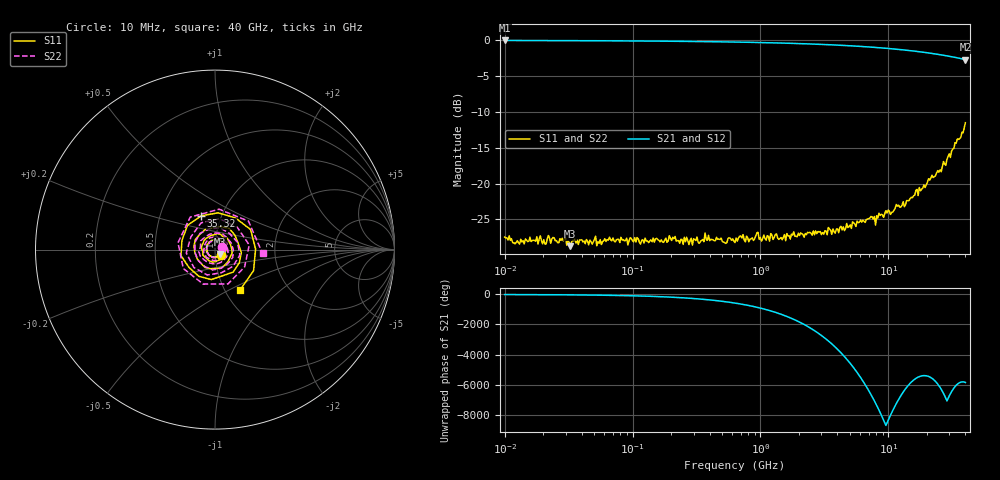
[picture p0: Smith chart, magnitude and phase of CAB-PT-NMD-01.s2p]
! CAL-ELEKTRA — DATOS SINTÉTICOS DE EJEMPLO: no son una medida real.
! Cable simulado CAB-PT-NMD-01: 0.63 m, 10 MHz – 40 GHz
# HZ S RI R 50
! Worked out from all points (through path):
!   401 points, 10 MHz to 40 GHz, reference 50 ohm
!   highest |S21| = -0.03 dB at 10 MHz (marker M1); lowest = -2.7 dB at 40 GHz (marker M2)
!   lowest |S11| = -28.7 dB at 32.61 MHz (marker M3), VSWR 1.08, Z = 52.8 - j2.55 ohm
!   |S11| at or under -10 dB: start of sweep to end of sweep
!   |S22| runs from -28.7 to -11.5 dB; largest |S21 - S12| = 0
!   S11 on the Smith chart (normalised r, x): 10 MHz: 1.06, -0.06; 35.32 GHz: 0.80, +0.32; 40 GHz: 1.17, -0.57
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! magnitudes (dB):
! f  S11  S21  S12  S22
! 10 MHz  -27.5  0.0  0.0  -27.5
! 12.56 MHz  -28.0  0.0  0.0  -28.0
! 18.63 MHz  -27.7  0.0  0.0  -27.7
! 20.24 MHz  -27.8  0.0  0.0  -27.8
! 22.92 MHz  -28.3  0.0  0.0  -28.3
! 32.61 MHz  -28.7  -0.1  -0.1  -28.7
! 40.12 MHz  -27.9  -0.1  -0.1  -27.9
! 54.75 MHz  -28.4  -0.1  -0.1  -28.4
! 67.37 MHz  -27.8  -0.1  -0.1  -27.8
! 160.9 MHz  -27.9  -0.1  -0.1  -27.9
! 632.5 MHz  -28.2  -0.3  -0.3  -28.2
! 701.5 MHz  -27.3  -0.3  -0.3  -27.3
! 778.2 MHz  -27.3  -0.3  -0.3  -27.3
! 957.5 MHz  -26.8  -0.3  -0.3  -26.8
! 1.42 GHz  -27.7  -0.4  -0.4  -27.7
! 2.537 GHz  -27.2  -0.5  -0.5  -27.2
! 3.922 GHz  -26.4  -0.7  -0.7  -26.4
! 10.18 GHz  -23.9  -1.2  -1.2  -23.9
! 13.89 GHz  -22.4  -1.4  -1.4  -22.4
! 24.83 GHz  -18.4  -2.0  -2.0  -18.4
! 35.32 GHz  -13.8  -2.5  -2.5  -13.8
! 40 GHz  -11.5  -2.7  -2.7  -11.5
